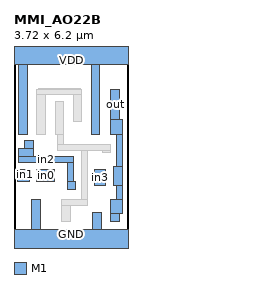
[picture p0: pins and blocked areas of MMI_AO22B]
MACRO MMI_AO22B
	CLASS CORE ;
	FOREIGN MMI_AO22B 0 0 ;
	SIZE 3.72 BY 6.2 ;
	SYMMETRY X Y ;
	SITE CORE1 ;
	PIN out
		DIRECTION output ;
		USE SIGNAL ;
		PORT
			LAYER M1 ;
			RECT 3.165 4.01 3.445 4.99 ;
			LAYER M1 ;
			RECT 3.165 3.52 3.555 4.01 ;
			LAYER M1 ;
			RECT 3.36 2.48 3.555 3.52 ;
			LAYER M1 ;
			RECT 3.245 1.86 3.555 2.48 ;
			LAYER M1 ;
			RECT 3.36 1.385 3.555 1.86 ;
			LAYER M1 ;
			RECT 3.165 0.935 3.555 1.385 ;
			LAYER M1 ;
			RECT 3.165 0.685 3.445 0.935 ;
		END
		AntennaDiffArea 0.91245 ;
	END out
	PIN in1
		DIRECTION input ;
		USE SIGNAL ;
		PORT
			LAYER M1 ;
			RECT 0.12 2.35 0.5 2.36 ;
			LAYER M1 ;
			RECT 0.12 2.07 0.53 2.35 ;
			LAYER M1 ;
			RECT 0.12 1.98 0.5 2.07 ;
		END
		AntennaGateArea 0.3465 ;
	END in1
	PIN GND
		DIRECTION inout ;
		USE GROUND ;
		PORT
			LAYER M1 ;
			RECT 0.58 0.42 0.86 1.385 ;
			LAYER M1 ;
			RECT 2.575 0.42 2.855 0.965 ;
			LAYER M1 ;
			RECT 0 -0.42 3.72 0.42 ;
		END
	END GND
	PIN in2
		DIRECTION input ;
		USE SIGNAL ;
		PORT
			LAYER M1 ;
			RECT 0.355 3.04 0.635 3.315 ;
			LAYER M1 ;
			RECT 0.16 2.8 0.635 3.04 ;
			LAYER M1 ;
			RECT 0.16 2.605 1.945 2.8 ;
			LAYER M1 ;
			RECT 1.75 1.98 1.945 2.605 ;
			LAYER M1 ;
			RECT 1.73 1.7 2.01 1.98 ;
		END
		AntennaGateArea 0.3465 ;
	END in2
	PIN VDD
		DIRECTION inout ;
		USE POWER ;
		PORT
			LAYER M1 ;
			RECT 0 5.78 3.72 6.62 ;
			LAYER M1 ;
			RECT 0.16 3.52 0.44 5.78 ;
			LAYER M1 ;
			RECT 2.52 3.52 2.8 5.78 ;
		END
	END VDD
	PIN in3
		DIRECTION input ;
		USE SIGNAL ;
		PORT
			LAYER M1 ;
			RECT 2.625 1.845 2.98 2.36 ;
		END
		AntennaGateArea 0.3465 ;
	END in3
	PIN in0
		DIRECTION input ;
		USE SIGNAL ;
		PORT
			LAYER M1 ;
			RECT 0.74 1.98 1.33 2.36 ;
		END
		AntennaGateArea 0.3465 ;
	END in0
	OBS
		LAYER M1 ;
		RECT 0.81 4.99 2.185 4.995 ;
		LAYER M1 ;
		RECT 0.75 4.8 2.21 4.99 ;
		LAYER M1 ;
		RECT 0.75 3.52 1.03 4.8 ;
		LAYER M1 ;
		RECT 1.34 3.52 1.62 4.58 ;
		LAYER M1 ;
		RECT 1.93 3.93 2.21 4.8 ;
		LAYER M1 ;
		RECT 1.42 3.195 1.615 3.52 ;
		LAYER M1 ;
		RECT 1.42 3 3.16 3.195 ;
		LAYER M1 ;
		RECT 2.21 1.385 2.4 3 ;
		LAYER M1 ;
		RECT 2.88 2.915 3.16 3 ;
		LAYER M1 ;
		RECT 1.56 1.195 2.4 1.385 ;
		LAYER M1 ;
		RECT 1.56 0.685 1.84 1.195 ;
	END
END MMI_AO22B
